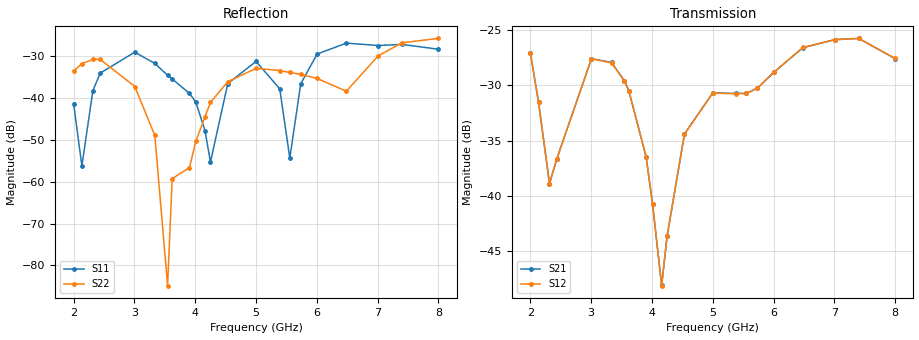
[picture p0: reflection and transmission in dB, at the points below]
!Agilent Technologies,E8364B,MY43040699,A.07.50.67
!Agilent E8364B: A.07.50.67
!Date: Friday, June 06, 2025 09:24:35
!Correction: S11(Full 2 Port(1,2))
!S21(Full 2 Port(1,2))
!S12(Full 2 Port(1,2))
!S22(Full 2 Port(1,2))
!S2P File: Measurements: S11, S21, S12, S22:
# Hz S  dB  R 50
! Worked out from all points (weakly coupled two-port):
!   401 points, 2 GHz to 8 GHz, reference 50 ohm
!   highest |S21| = -25.77 dB at 7.4 GHz (marker M1); lowest = -48.1 dB at 4.16 GHz (marker M2)
!   lowest |S11| = -56.2 dB at 2.135 GHz (marker M3), VSWR 1.00, Z = 50.1 + j0.1 ohm
!   |S11| at or under -10 dB: start of sweep to end of sweep
!   |S22| runs from -84.8 to -25.5 dB; largest |S21 - S12| = 0.00032
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2e9  -41.45 -6.9  -27.08 31.4  -27.08 31.5  -33.52 -11.4
2.135e9  -56.21 40.2  -31.53 20.4  -31.54 20.5  -31.76 -22.1
2.315e9  -38.27 105.4  -38.87 44.5  -38.89 44.7  -30.75 -41.3
2.435e9  -34.04 90.0  -36.64 79.0  -36.65 79.0  -30.72 -54.1
3.005e9  -29.01 15.6  -27.59 22.2  -27.61 22.2  -37.22 -118.0
3.335e9  -31.71 -15.2  -27.93 -30.0  -27.97 -30.0  -48.92 -154.7
3.545e9  -34.56 -25.5  -29.57 -64.9  -29.61 -64.8  -84.84 -41.0
3.62e9  -35.40 -27.9  -30.47 -77.8  -30.51 -77.6  -59.26 16.7
3.905e9  -38.88 -35.4  -36.46 -131.5  -36.51 -131.3  -56.60 69.0
4.01e9  -40.98 -44.5  -40.68 -158.5  -40.73 -158.3  -50.28 73.3
4.16e9  -47.76 -74.5  -48.06 108.0  -48.10 108.2  -44.47 73.4
4.25e9  -55.28 -148.3  -43.59 44.8  -43.63 45.2  -41.02 66.3
4.535e9  -36.51 97.1  -34.39 -24.2  -34.42 -23.7  -36.07 30.7
5e9  -31.22 30.1  -30.69 -94.6  -30.71 -94.2  -32.88 -33.5
5.39e9  -37.78 -29.7  -30.74 -137.2  -30.76 -136.7  -33.40 -99.4
5.555e9  -54.34 -121.2  -30.73 -150.1  -30.74 -149.7  -33.85 -127.7
5.735e9  -36.57 119.5  -30.26 -162.7  -30.25 -162.5  -34.32 -158.6
6.005e9  -29.45 82.5  -28.83 174.9  -28.81 175.2  -35.30 161.6
6.485e9  -26.85 35.7  -26.60 123.2  -26.58 123.5  -38.35 166.0
7.01e9  -27.42 13.8  -25.88 64.1  -25.87 64.3  -29.87 163.6
7.4e9  -27.15 -2.7  -25.77 22.5  -25.76 22.6  -26.78 140.3
8e9  -28.31 -34.8  -27.59 -42.5  -27.56 -42.4  -25.71 103.5
